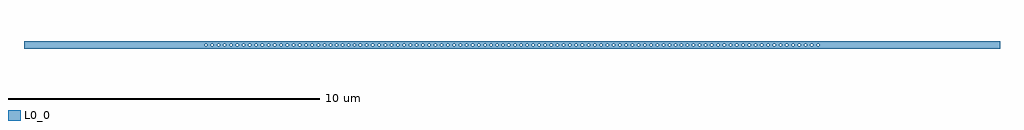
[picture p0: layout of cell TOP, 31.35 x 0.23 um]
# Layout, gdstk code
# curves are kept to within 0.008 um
import gdstk
lib = gdstk.Library(unit=1e-6, precision=1e-09)
def P(c, l, *ps):  # polygons
    for p in ps: c.add(gdstk.Polygon(p, *l))
L0_0 = (0, 0)

top = lib.new_cell('TOP')
P(top, L0_0, [(0,0),(0,0),(0,0),(0,0)],
  [(-8.011,0.042),(-8.011,0.113),(-15.675,0.113),(-15.675,0.044),(-8.026,0.044)],
  [(-8.011,-0.042),(-8.04,-0.04),(-8.066,-0.007),(-8.061,0.021),(-8.026,0.044),(-8.227,0.044),(-8.189,0.027),(-8.18,0),(-8.189,-0.027),(-8.227,-0.044),(-8.253,-0.032),(-8.267,-0.007),(-8.262,0.021),(-8.227,0.044),(-8.428,0.044),(-8.39,0.027),(-8.381,0),(-8.39,-0.027),(-8.428,-0.044),(-8.454,-0.032),(-8.468,-0.007),(-8.463,0.021),(-8.428,0.044),(-8.629,0.044),(-8.591,0.027),(-8.582,0),(-8.591,-0.027),(-8.629,-0.044),(-8.655,-0.032),(-8.669,-0.007),(-8.664,0.021),(-8.629,0.044),(-8.83,0.044),(-8.792,0.027),(-8.783,0),(-8.792,-0.027),(-8.83,-0.044),(-8.856,-0.032),(-8.87,-0.007),(-8.865,0.021),(-8.83,0.044),(-9.031,0.044),(-8.993,0.027),(-8.984,0),(-8.993,-0.027),(-9.031,-0.044),(-9.057,-0.032),(-9.071,-0.007),(-9.066,0.021),(-9.031,0.044),(-9.232,0.044),(-9.194,0.027),(-9.185,0),(-9.194,-0.027),(-9.232,-0.044),(-9.258,-0.032),(-9.272,-0.007),(-9.267,0.021),(-9.232,0.044),(-9.433,0.044),(-9.395,0.027),(-9.386,0),(-9.395,-0.027),(-9.433,-0.044),(-9.459,-0.032),(-9.473,-0.007),(-9.468,0.021),(-9.433,0.044),(-9.634,0.044),(-9.596,0.027),(-9.587,0),(-9.596,-0.027),(-9.634,-0.044),(-9.66,-0.032),(-9.674,-0.007),(-9.669,0.021),(-9.634,0.044),(-9.835,0.044),(-9.797,0.027),(-9.788,0),(-9.797,-0.027),(-9.835,-0.044),(-9.861,-0.032),(-9.875,-0.007),(-9.87,0.021),(-9.835,0.044),(-15.675,0.044),(-15.675,-0.113),(-8.011,-0.113)],
  [(-6.208,0.042),(-6.196,0.036),(-6.185,0.027),(-6.178,0.014),(-6.178,0.113),(-8.011,0.113),(-8.011,0.044),(-6.223,0.044)],
  [(-6.178,-0.014),(-6.196,-0.036),(-6.223,-0.044),(-6.258,-0.021),(-6.258,0.021),(-6.223,0.044),(-6.421,0.044),(-6.384,0.027),(-6.374,0),(-6.384,-0.027),(-6.421,-0.044),(-6.448,-0.032),(-6.461,-0.007),(-6.448,0.032),(-6.421,0.044),(-6.621,0.044),(-6.583,0.027),(-6.573,0),(-6.583,-0.027),(-6.621,-0.044),(-6.647,-0.032),(-6.66,-0.007),(-6.647,0.032),(-6.621,0.044),(-6.821,0.044),(-6.783,0.027),(-6.773,0),(-6.783,-0.027),(-6.821,-0.044),(-6.847,-0.032),(-6.86,-0.007),(-6.856,0.021),(-6.821,0.044),(-7.021,0.044),(-6.984,0.027),(-6.974,0),(-6.984,-0.027),(-7.021,-0.044),(-7.048,-0.032),(-7.061,-0.007),(-7.048,0.032),(-7.021,0.044),(-7.222,0.044),(-7.184,0.027),(-7.175,0),(-7.184,-0.027),(-7.222,-0.044),(-7.249,-0.032),(-7.262,-0.007),(-7.249,0.032),(-7.222,0.044),(-7.423,0.044),(-7.385,0.027),(-7.376,0),(-7.385,-0.027),(-7.423,-0.044),(-7.45,-0.032),(-7.463,-0.007),(-7.45,0.032),(-7.423,0.044),(-7.624,0.044),(-7.586,0.027),(-7.577,0),(-7.586,-0.027),(-7.624,-0.044),(-7.65,-0.032),(-7.664,-0.007),(-7.659,0.021),(-7.624,0.044),(-7.825,0.044),(-7.787,0.027),(-7.778,0),(-7.787,-0.027),(-7.825,-0.044),(-7.851,-0.032),(-7.865,-0.007),(-7.86,0.021),(-7.825,0.044),(-8.011,0.044),(-7.988,0.027),(-7.979,0),(-7.988,-0.027),(-8.011,-0.042),(-8.011,-0.113),(-6.178,-0.113)],
  [(-4.459,0.042),(-4.446,0.036),(-4.436,0.027),(-4.436,0.113),(-6.178,0.113),(-6.178,0.044),(-4.473,0.044)],
  [(-4.436,-0.027),(-4.473,-0.044),(-4.508,-0.021),(-4.508,0.021),(-4.473,0.044),(-4.674,0.044),(-4.637,0.027),(-4.627,0),(-4.637,-0.027),(-4.674,-0.044),(-4.701,-0.032),(-4.714,-0.007),(-4.701,0.032),(-4.674,0.044),(-4.875,0.044),(-4.838,0.027),(-4.828,0),(-4.838,-0.027),(-4.875,-0.044),(-4.902,-0.032),(-4.915,-0.007),(-4.902,0.032),(-4.875,0.044),(-5.064,0.044),(-5.027,0.027),(-5.017,0),(-5.027,-0.027),(-5.064,-0.044),(-5.091,-0.032),(-5.104,-0.007),(-5.091,0.032),(-5.064,0.044),(-5.254,0.044),(-5.216,0.027),(-5.206,0),(-5.216,-0.027),(-5.254,-0.044),(-5.28,-0.032),(-5.293,-0.007),(-5.289,0.021),(-5.254,0.044),(-5.444,0.044),(-5.406,0.027),(-5.397,0),(-5.406,-0.027),(-5.444,-0.044),(-5.471,-0.032),(-5.484,-0.007),(-5.471,0.032),(-5.444,0.044),(-5.636,0.044),(-5.598,0.027),(-5.589,0),(-5.598,-0.027),(-5.636,-0.044),(-5.663,-0.032),(-5.676,-0.007),(-5.663,0.032),(-5.636,0.044),(-5.83,0.044),(-5.792,0.027),(-5.783,0),(-5.792,-0.027),(-5.83,-0.044),(-5.857,-0.032),(-5.87,-0.007),(-5.857,0.032),(-5.83,0.044),(-6.026,0.044),(-5.988,0.027),(-5.978,0),(-5.988,-0.027),(-6.026,-0.044),(-6.052,-0.032),(-6.065,-0.007),(-6.052,0.032),(-6.026,0.044),(-6.178,0.044),(-6.178,-0.113),(-4.436,-0.113)],
  [(-2.65,0.042),(-2.637,0.036),(-2.627,0.027),(-2.627,0.113),(-4.436,0.113),(-4.436,0.044),(-2.664,0.044)],
  [(-2.627,-0.027),(-2.664,-0.044),(-2.699,-0.021),(-2.699,0.021),(-2.664,0.044),(-2.865,0.044),(-2.828,0.027),(-2.818,0),(-2.828,-0.027),(-2.865,-0.044),(-2.892,-0.032),(-2.905,-0.007),(-2.892,0.032),(-2.865,0.044),(-3.066,0.044),(-3.029,0.027),(-3.019,0),(-3.029,-0.027),(-3.066,-0.044),(-3.093,-0.032),(-3.106,-0.007),(-3.093,0.032),(-3.066,0.044),(-3.267,0.044),(-3.23,0.027),(-3.22,0),(-3.23,-0.027),(-3.267,-0.044),(-3.294,-0.032),(-3.307,-0.007),(-3.294,0.032),(-3.267,0.044),(-3.468,0.044),(-3.431,0.027),(-3.421,0),(-3.431,-0.027),(-3.468,-0.044),(-3.495,-0.032),(-3.508,-0.007),(-3.495,0.032),(-3.468,0.044),(-3.669,0.044),(-3.632,0.027),(-3.622,0),(-3.632,-0.027),(-3.669,-0.044),(-3.696,-0.032),(-3.709,-0.007),(-3.696,0.032),(-3.669,0.044),(-3.87,0.044),(-3.833,0.027),(-3.823,0),(-3.833,-0.027),(-3.87,-0.044),(-3.897,-0.032),(-3.91,-0.007),(-3.897,0.032),(-3.87,0.044),(-4.071,0.044),(-4.034,0.027),(-4.024,0),(-4.034,-0.027),(-4.071,-0.044),(-4.098,-0.032),(-4.111,-0.007),(-4.098,0.032),(-4.071,0.044),(-4.272,0.044),(-4.235,0.027),(-4.225,0),(-4.235,-0.027),(-4.272,-0.044),(-4.299,-0.032),(-4.312,-0.007),(-4.299,0.032),(-4.272,0.044),(-4.436,0.044),(-4.426,0),(-4.436,-0.027),(-4.436,-0.113),(-2.627,-0.113)],
  [(-0.856,0.042),(-0.844,0.036),(-0.833,0.027),(-0.826,0.014),(-0.826,0.113),(-2.627,0.113),(-2.627,0.044),(-0.87,0.044)],
  [(-0.826,-0.014),(-0.856,-0.042),(-0.897,-0.032),(-0.91,0.007),(-0.897,0.032),(-0.87,0.044),(-1.066,0.044),(-1.028,0.027),(-1.019,0),(-1.028,-0.027),(-1.066,-0.044),(-1.093,-0.032),(-1.106,-0.007),(-1.093,0.032),(-1.066,0.044),(-1.263,0.044),(-1.226,0.027),(-1.216,0),(-1.226,-0.027),(-1.263,-0.044),(-1.29,-0.032),(-1.303,-0.007),(-1.29,0.032),(-1.263,0.044),(-1.462,0.044),(-1.424,0.027),(-1.414,0),(-1.424,-0.027),(-1.462,-0.044),(-1.488,-0.032),(-1.501,-0.007),(-1.497,0.021),(-1.462,0.044),(-1.661,0.044),(-1.624,0.027),(-1.614,0),(-1.624,-0.027),(-1.661,-0.044),(-1.688,-0.032),(-1.701,-0.007),(-1.688,0.032),(-1.661,0.044),(-1.861,0.044),(-1.824,0.027),(-1.814,0),(-1.824,-0.027),(-1.861,-0.044),(-1.888,-0.032),(-1.901,-0.007),(-1.888,0.032),(-1.861,0.044),(-2.062,0.044),(-2.024,0.027),(-2.015,0),(-2.024,-0.027),(-2.062,-0.044),(-2.088,-0.032),(-2.102,-0.007),(-2.097,0.021),(-2.062,0.044),(-2.263,0.044),(-2.225,0.027),(-2.215,0),(-2.225,-0.027),(-2.263,-0.044),(-2.289,-0.032),(-2.302,-0.007),(-2.289,0.032),(-2.263,0.044),(-2.463,0.044),(-2.426,0.027),(-2.416,0),(-2.426,-0.027),(-2.463,-0.044),(-2.49,-0.032),(-2.503,-0.007),(-2.49,0.032),(-2.463,0.044),(-2.627,0.044),(-2.617,0),(-2.627,-0.027),(-2.627,-0.113),(-0.826,-0.113)],
  [(0.878,0.042),(0.891,0.036),(0.901,0.027),(0.909,0.014),(0.909,0.113),(-0.826,0.113),(-0.826,0.044),(0.864,0.044)],
  [(0.909,-0.014),(0.878,-0.042),(0.837,-0.032),(0.824,0.007),(0.837,0.032),(0.864,0.044),(0.67,0.044),(0.708,0.027),(0.717,0),(0.708,-0.027),(0.67,-0.044),(0.643,-0.032),(0.63,-0.007),(0.643,0.032),(0.67,0.044),(0.478,0.044),(0.516,0.027),(0.525,0),(0.516,-0.027),(0.478,-0.044),(0.451,-0.032),(0.438,-0.007),(0.451,0.032),(0.478,0.044),(0.288,0.044),(0.325,0.027),(0.335,0),(0.325,-0.027),(0.288,-0.044),(0.261,-0.032),(0.248,-0.007),(0.261,0.032),(0.288,0.044),(0.098,0.044),(0.136,0.027),(0.145,0),(0.136,-0.027),(0.098,-0.044),(0.071,-0.032),(0.058,-0.007),(0.071,0.032),(0.098,0.044),(-0.105,0.044),(-0.067,0.027),(-0.058,0),(-0.067,-0.027),(-0.105,-0.044),(-0.132,-0.032),(-0.145,-0.007),(-0.132,0.032),(-0.105,0.044),(-0.294,0.044),(-0.257,0.027),(-0.247,0),(-0.257,-0.027),(-0.294,-0.044),(-0.321,-0.032),(-0.334,-0.007),(-0.321,0.032),(-0.294,0.044),(-0.485,0.044),(-0.447,0.027),(-0.437,0),(-0.447,-0.027),(-0.485,-0.044),(-0.511,-0.032),(-0.524,-0.007),(-0.511,0.032),(-0.485,0.044),(-0.677,0.044),(-0.639,0.027),(-0.629,0),(-0.639,-0.027),(-0.677,-0.044),(-0.703,-0.032),(-0.716,-0.007),(-0.703,0.032),(-0.677,0.044),(-0.826,0.044),(-0.826,-0.113),(0.909,-0.113)],
  [(2.672,0.042),(2.685,0.036),(2.695,0.027),(2.695,0.113),(0.909,0.113),(0.909,0.044),(2.658,0.044)],
  [(2.695,-0.113),(2.695,-0.027),(2.658,-0.044),(2.631,-0.032),(2.618,-0.007),(2.631,0.032),(2.658,0.044),(2.457,0.044),(2.494,0.027),(2.504,0),(2.494,-0.027),(2.457,-0.044),(2.43,-0.032),(2.417,-0.007),(2.43,0.032),(2.457,0.044),(2.256,0.044),(2.293,0.027),(2.303,0),(2.293,-0.027),(2.256,-0.044),(2.229,-0.032),(2.216,-0.007),(2.229,0.032),(2.256,0.044),(2.055,0.044),(2.093,0.027),(2.102,0),(2.093,-0.027),(2.055,-0.044),(2.028,-0.032),(2.015,-0.007),(2.028,0.032),(2.055,0.044),(1.855,0.044),(1.892,0.027),(1.902,0),(1.892,-0.027),(1.855,-0.044),(1.828,-0.032),(1.815,-0.007),(1.828,0.032),(1.855,0.044),(1.654,0.044),(1.692,0.027),(1.702,0),(1.692,-0.027),(1.654,-0.044),(1.628,-0.032),(1.615,-0.007),(1.628,0.032),(1.654,0.044),(1.455,0.044),(1.493,0.027),(1.502,0),(1.493,-0.027),(1.455,-0.044),(1.428,-0.032),(1.415,-0.007),(1.428,0.032),(1.455,0.044),(1.257,0.044),(1.294,0.027),(1.304,0),(1.294,-0.027),(1.257,-0.044),(1.23,-0.032),(1.217,-0.007),(1.23,0.032),(1.257,0.044),(1.059,0.044),(1.097,0.027),(1.107,0),(1.097,-0.027),(1.059,-0.044),(1.033,-0.032),(1.02,-0.007),(1.033,0.032),(1.059,0.044),(0.909,0.044),(0.909,-0.113)],
  [(4.481,0.042),(4.494,0.036),(4.504,0.027),(4.504,0.113),(2.695,0.113),(2.695,0.044),(4.467,0.044)],
  [(4.504,-0.027),(4.467,-0.044),(4.432,-0.021),(4.432,0.021),(4.467,0.044),(4.266,0.044),(4.303,0.027),(4.313,0),(4.303,-0.027),(4.266,-0.044),(4.239,-0.032),(4.226,-0.007),(4.239,0.032),(4.266,0.044),(4.065,0.044),(4.102,0.027),(4.112,0),(4.102,-0.027),(4.065,-0.044),(4.038,-0.032),(4.025,-0.007),(4.038,0.032),(4.065,0.044),(3.864,0.044),(3.901,0.027),(3.911,0),(3.901,-0.027),(3.864,-0.044),(3.837,-0.032),(3.824,-0.007),(3.837,0.032),(3.864,0.044),(3.663,0.044),(3.7,0.027),(3.71,0),(3.7,-0.027),(3.663,-0.044),(3.636,-0.032),(3.623,-0.007),(3.636,0.032),(3.663,0.044),(3.462,0.044),(3.499,0.027),(3.509,0),(3.499,-0.027),(3.462,-0.044),(3.435,-0.032),(3.422,-0.007),(3.435,0.032),(3.462,0.044),(3.261,0.044),(3.298,0.027),(3.308,0),(3.298,-0.027),(3.261,-0.044),(3.234,-0.032),(3.221,-0.007),(3.234,0.032),(3.261,0.044),(3.06,0.044),(3.097,0.027),(3.107,0),(3.097,-0.027),(3.06,-0.044),(3.033,-0.032),(3.02,-0.007),(3.033,0.032),(3.06,0.044),(2.859,0.044),(2.896,0.027),(2.906,0),(2.896,-0.027),(2.859,-0.044),(2.832,-0.032),(2.819,-0.007),(2.832,0.032),(2.859,0.044),(2.695,0.044),(2.705,0),(2.695,-0.027),(2.695,-0.113),(4.504,-0.113)],
  [(6.23,0.042),(6.243,0.036),(6.243,0.113),(4.504,0.113),(4.504,0.044),(6.216,0.044)],
  [(6.243,-0.036),(6.202,-0.04),(6.176,-0.007),(6.189,0.032),(6.216,0.044),(6.019,0.044),(6.056,0.027),(6.066,0),(6.056,-0.027),(6.019,-0.044),(5.992,-0.032),(5.979,-0.007),(5.992,0.032),(6.019,0.044),(5.823,0.044),(5.861,0.027),(5.87,0),(5.861,-0.027),(5.823,-0.044),(5.797,-0.032),(5.783,-0.007),(5.788,0.021),(5.823,0.044),(5.629,0.044),(5.667,0.027),(5.677,0),(5.667,-0.027),(5.629,-0.044),(5.603,-0.032),(5.59,-0.007),(5.603,0.032),(5.629,0.044),(5.437,0.044),(5.475,0.027),(5.485,0),(5.475,-0.027),(5.437,-0.044),(5.411,-0.032),(5.398,-0.007),(5.411,0.032),(5.437,0.044),(5.247,0.044),(5.285,0.027),(5.294,0),(5.285,-0.027),(5.247,-0.044),(5.22,-0.032),(5.207,-0.007),(5.22,0.032),(5.247,0.044),(5.058,0.044),(5.095,0.027),(5.105,0),(5.095,-0.027),(5.058,-0.044),(5.031,-0.032),(5.018,-0.007),(5.031,0.032),(5.058,0.044),(4.869,0.044),(4.906,0.027),(4.916,0),(4.906,-0.027),(4.869,-0.044),(4.842,-0.032),(4.829,-0.007),(4.842,0.032),(4.869,0.044),(4.668,0.044),(4.705,0.027),(4.715,0),(4.705,-0.027),(4.668,-0.044),(4.641,-0.032),(4.628,-0.007),(4.641,0.032),(4.668,0.044),(4.504,0.044),(4.514,0),(4.504,-0.027),(4.504,-0.113),(6.243,-0.113)],
  [(8.033,0.042),(8.046,0.036),(8.057,0.027),(8.064,0.014),(8.064,0.113),(6.243,0.113),(6.243,0.044),(8.019,0.044)],
  [(8.064,-0.014),(8.033,-0.042),(7.992,-0.032),(7.979,0.007),(7.992,0.032),(8.019,0.044),(7.818,0.044),(7.856,0.027),(7.865,0),(7.856,-0.027),(7.818,-0.044),(7.791,-0.032),(7.778,-0.007),(7.791,0.032),(7.818,0.044),(7.617,0.044),(7.655,0.027),(7.664,0),(7.655,-0.027),(7.617,-0.044),(7.59,-0.032),(7.577,-0.007),(7.59,0.032),(7.617,0.044),(7.416,0.044),(7.454,0.027),(7.463,0),(7.454,-0.027),(7.416,-0.044),(7.389,-0.032),(7.376,-0.007),(7.389,0.032),(7.416,0.044),(7.215,0.044),(7.253,0.027),(7.263,0),(7.253,-0.027),(7.215,-0.044),(7.189,-0.032),(7.176,-0.007),(7.18,0.021),(7.215,0.044),(7.015,0.044),(7.052,0.027),(7.062,0),(7.052,-0.027),(7.015,-0.044),(6.988,-0.032),(6.975,-0.007),(6.988,0.032),(7.015,0.044),(6.814,0.044),(6.852,0.027),(6.861,0),(6.852,-0.027),(6.814,-0.044),(6.787,-0.032),(6.774,-0.007),(6.787,0.032),(6.814,0.044),(6.614,0.044),(6.652,0.027),(6.661,0),(6.652,-0.027),(6.614,-0.044),(6.587,-0.032),(6.574,-0.007),(6.587,0.032),(6.614,0.044),(6.414,0.044),(6.452,0.027),(6.462,0),(6.452,-0.027),(6.414,-0.044),(6.388,-0.032),(6.375,-0.007),(6.388,0.032),(6.414,0.044),(6.243,0.044),(6.263,0),(6.243,-0.036),(6.243,-0.113),(8.064,-0.113)],
  [(8.066,0),(8.18,-0.007),(8.193,0.032),(8.22,0.044),(8.258,0.027),(8.265,-0.007),(8.381,-0.007),(8.394,0.032),(8.421,0.044),(8.459,0.027),(8.466,-0.007),(8.582,-0.007),(8.595,0.032),(8.622,0.044),(8.66,0.027),(8.667,-0.007),(8.783,-0.007),(8.796,0.032),(8.823,0.044),(8.861,0.027),(8.87,0),(8.861,-0.027),(8.823,-0.044),(8.796,-0.032),(8.783,-0.007),(8.667,-0.007),(8.66,-0.027),(8.622,-0.044),(8.595,-0.032),(8.582,-0.007),(8.466,-0.007),(8.459,-0.027),(8.421,-0.044),(8.394,-0.032),(8.381,-0.007),(8.265,-0.007),(8.258,-0.027),(8.22,-0.044),(8.193,-0.032),(8.18,-0.007),(8.064,-0.007),(8.064,-0.113),(9.024,-0.113),(9.024,-0.044),(8.997,-0.032),(8.984,-0.007),(8.997,0.032),(9.024,0.044),(9.024,0.113),(8.064,0.113)],
  [(9.062,-0.027),(9.024,-0.044),(9.024,-0.113),(15.675,-0.113),(15.675,0.113),(9.024,0.113),(9.024,0.044),(9.062,0.027),(9.069,-0.007),(9.185,-0.007),(9.198,0.032),(9.225,0.044),(9.263,0.027),(9.27,-0.007),(9.386,-0.007),(9.399,0.032),(9.426,0.044),(9.464,0.027),(9.471,-0.007),(9.587,-0.007),(9.6,0.032),(9.627,0.044),(9.665,0.027),(9.672,-0.007),(9.788,-0.007),(9.801,0.032),(9.828,0.044),(9.855,0.036),(9.873,0.014),(9.866,-0.027),(9.828,-0.044),(9.801,-0.032),(9.788,-0.007),(9.672,-0.007),(9.665,-0.027),(9.627,-0.044),(9.6,-0.032),(9.587,-0.007),(9.471,-0.007),(9.464,-0.027),(9.426,-0.044),(9.399,-0.032),(9.386,-0.007),(9.27,-0.007),(9.263,-0.027),(9.225,-0.044),(9.198,-0.032),(9.185,-0.007),(9.069,-0.007)])

lib.write_gds('TOP.gds')
